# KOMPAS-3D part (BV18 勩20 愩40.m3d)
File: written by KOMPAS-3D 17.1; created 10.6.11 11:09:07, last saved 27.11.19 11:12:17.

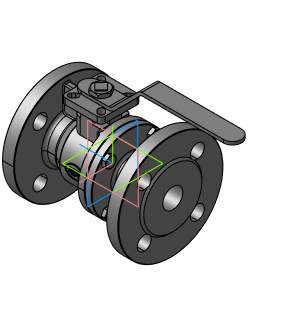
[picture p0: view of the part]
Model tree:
1. Плоскость XY
2. Плоскость ZX
3. Плоскость ZY
4. Ось X
5. Ось Y
6. Ось Z
7. Начало координат
8. Операция без истории:4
